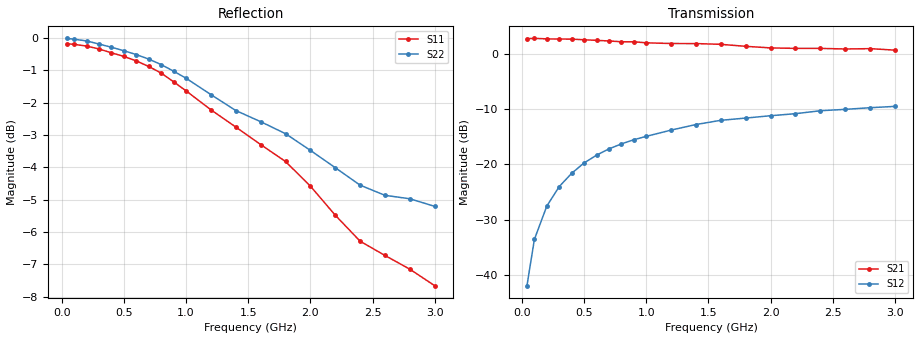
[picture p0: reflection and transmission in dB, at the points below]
! Filename:  BFS25AC.S2P  Version:  4.0
! NXP part #: BFS25A  Date: Jun 1994
! Bias condition: Vce=1V, Ic=0.50mA
#  MHz  S  MA  R  50
! Freq  S11  S21  S12  S22  !GUM [dB]
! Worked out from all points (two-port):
!   21 points, 40 MHz to 3 GHz, reference 50 ohm
!   highest |S21| = 2.77 dB at 100 MHz (marker M1); lowest = 0.6 dB at 3 GHz (marker M2)
!   |S21| within 3 dB of the highest: start of sweep to end of sweep
!   lowest |S11| = -7.7 dB at 3 GHz (marker M3), VSWR 2.41, Z = 47.1 - j44 ohm
!   |S11| at or under -10 dB: nowhere
!   |S22| runs from -5.2 to 0.0 dB; largest |S21 - S12| = 1.4
!   S11 on the Smith chart (normalised r, x): 40 MHz: 44, -47; 500 MHz: 1.60, -6.70; 900 MHz: 1.27, -3.71; 1.4 GHz: 1.09, -2.21; 2.2 GHz: 1.07, -1.30; 3 GHz: 0.94, -0.88
40  0.979 -1.3  1.367 177.4  0.008 89.5  0.998 -1.3
100  0.977 -3.2  1.376 173.8  0.021 86.2  0.995 -3.1
200  0.971 -6.4  1.362 167.8  0.042 82.6  0.989 -6.3
300  0.961 -9.7  1.356 162.3  0.063 79.6  0.978 -9.5
400  0.948 -13.1  1.355 156.9  0.083 77.1  0.967 -12.6
500  0.936 -16.1  1.336 152.2  0.103 74.6  0.955 -15.8
600  0.921 -19.1  1.32 147.3  0.121 72.4  0.942 -18.6
700  0.903 -22.0  1.303 142.6  0.138 70.2  0.927 -21.2
800  0.882 -24.6  1.282 138.0  0.153 68.0  0.909 -23.5
900  0.855 -27.3  1.281 133.1  0.167 65.8  0.888 -25.6
1000  0.828 -29.8  1.254 128.7  0.179 63.4  0.866 -27.7
1200  0.774 -35.5  1.236 120.6  0.204 58.8  0.817 -32.2
1400  0.728 -41.1  1.235 113.2  0.229 55.5  0.772 -36.4
1600  0.684 -45.5  1.215 106.8  0.25 52.3  0.742 -40.2
1800  0.644 -48.5  1.166 101.7  0.262 50.7  0.711 -43.3
2000  0.59 -51.2  1.128 95.2  0.275 48.3  0.67 -45.6
2200  0.532 -54.8  1.117 89.8  0.287 46.5  0.63 -48.4
2400  0.485 -59.7  1.117 83.3  0.305 44.1  0.592 -52.5
2600  0.461 -65.6  1.103 79.8  0.314 42.2  0.571 -56.7
2800  0.439 -68.9  1.111 76.5  0.325 42.2  0.564 -59.5
3000  0.414 -69.4  1.077 72.7  0.334 41.4  0.549 -61.1
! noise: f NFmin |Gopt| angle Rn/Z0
500  1.6  0.902  3  2.4
1000  1.8  0.8  10  2.4
2000  2  0.846  26  1.4
